# Generated by OpenFakeRAM
VERSION 5.7 ;
BUSBITCHARS "[]" ;
PROPERTYDEFINITIONS
  MACRO width INTEGER ;
  MACRO depth INTEGER ;
  MACRO banks INTEGER ;
END PROPERTYDEFINITIONS
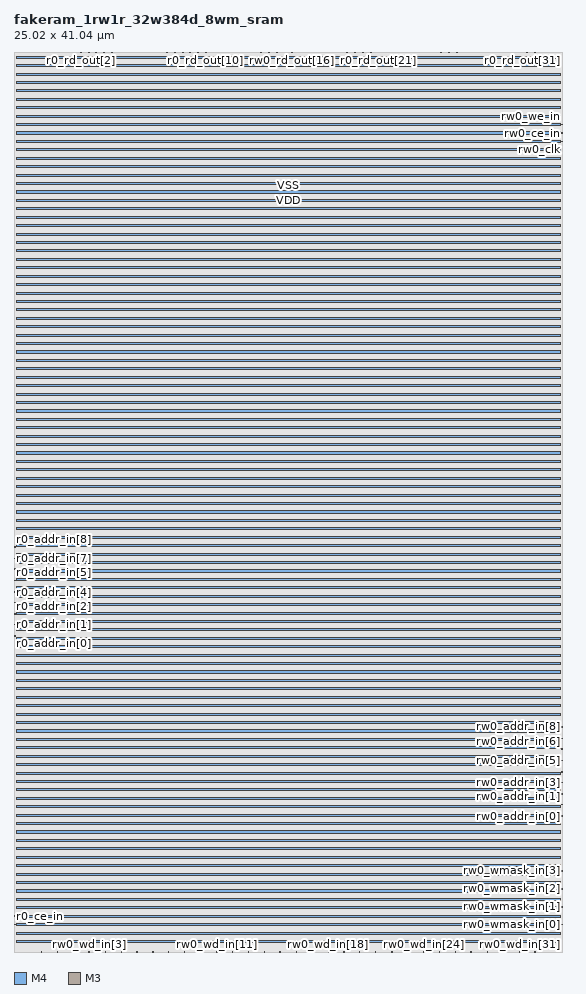
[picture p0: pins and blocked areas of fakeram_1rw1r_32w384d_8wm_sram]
MACRO fakeram_1rw1r_32w384d_8wm_sram
  PROPERTY width 32 ;
  PROPERTY depth 384 ;
  PROPERTY banks 1 ;
  FOREIGN fakeram_1rw1r_32w384d_8wm_sram 0 0 ;
  SYMMETRY X Y R90 ;
  SIZE 25.020 BY 41.040 ;
  CLASS BLOCK ;
  PIN r0_clk
    DIRECTION INPUT ;
    USE SIGNAL ;
    SHAPE ABUTMENT ;
    PORT
      LAYER M4 ;
      RECT 0.000 1.236 0.048 1.260 ;
    END
  END r0_clk
  PIN r0_ce_in
    DIRECTION INPUT ;
    USE SIGNAL ;
    SHAPE ABUTMENT ;
    PORT
      LAYER M4 ;
      RECT 0.000 1.620 0.048 1.644 ;
    END
  END r0_ce_in
  PIN r0_addr_in[0]
    DIRECTION INPUT ;
    USE SIGNAL ;
    SHAPE ABUTMENT ;
    PORT
      LAYER M4 ;
      RECT 0.000 14.388 0.048 14.412 ;
    END
  END r0_addr_in[0]
  PIN r0_addr_in[1]
    DIRECTION INPUT ;
    USE SIGNAL ;
    SHAPE ABUTMENT ;
    PORT
      LAYER M4 ;
      RECT 0.000 14.916 0.048 14.940 ;
    END
  END r0_addr_in[1]
  PIN r0_addr_in[2]
    DIRECTION INPUT ;
    USE SIGNAL ;
    SHAPE ABUTMENT ;
    PORT
      LAYER M4 ;
      RECT 0.000 15.396 0.048 15.420 ;
    END
  END r0_addr_in[2]
  PIN r0_addr_in[3]
    DIRECTION INPUT ;
    USE SIGNAL ;
    SHAPE ABUTMENT ;
    PORT
      LAYER M4 ;
      RECT 0.000 15.924 0.048 15.948 ;
    END
  END r0_addr_in[3]
  PIN r0_addr_in[4]
    DIRECTION INPUT ;
    USE SIGNAL ;
    SHAPE ABUTMENT ;
    PORT
      LAYER M4 ;
      RECT 0.000 16.404 0.048 16.428 ;
    END
  END r0_addr_in[4]
  PIN r0_addr_in[5]
    DIRECTION INPUT ;
    USE SIGNAL ;
    SHAPE ABUTMENT ;
    PORT
      LAYER M4 ;
      RECT 0.000 16.932 0.048 16.956 ;
    END
  END r0_addr_in[5]
  PIN r0_addr_in[6]
    DIRECTION INPUT ;
    USE SIGNAL ;
    SHAPE ABUTMENT ;
    PORT
      LAYER M4 ;
      RECT 0.000 17.460 0.048 17.484 ;
    END
  END r0_addr_in[6]
  PIN r0_addr_in[7]
    DIRECTION INPUT ;
    USE SIGNAL ;
    SHAPE ABUTMENT ;
    PORT
      LAYER M4 ;
      RECT 0.000 17.940 0.048 17.964 ;
    END
  END r0_addr_in[7]
  PIN r0_addr_in[8]
    DIRECTION INPUT ;
    USE SIGNAL ;
    SHAPE ABUTMENT ;
    PORT
      LAYER M4 ;
      RECT 0.000 18.468 0.048 18.492 ;
    END
  END r0_addr_in[8]
  PIN rw0_rd_out[0]
    DIRECTION OUTPUT ;
    USE SIGNAL ;
    SHAPE ABUTMENT ;
    PORT
      LAYER M3 ;
      RECT 1.251 41.004 1.269 41.040 ;
    END
  END rw0_rd_out[0]
  PIN r0_rd_out[0]
    DIRECTION OUTPUT ;
    USE SIGNAL ;
    SHAPE ABUTMENT ;
    PORT
      LAYER M3 ;
      RECT 1.611 41.004 1.629 41.040 ;
    END
  END r0_rd_out[0]
  PIN rw0_rd_out[1]
    DIRECTION OUTPUT ;
    USE SIGNAL ;
    SHAPE ABUTMENT ;
    PORT
      LAYER M3 ;
      RECT 1.971 41.004 1.989 41.040 ;
    END
  END rw0_rd_out[1]
  PIN r0_rd_out[1]
    DIRECTION OUTPUT ;
    USE SIGNAL ;
    SHAPE ABUTMENT ;
    PORT
      LAYER M3 ;
      RECT 2.331 41.004 2.349 41.040 ;
    END
  END r0_rd_out[1]
  PIN rw0_rd_out[2]
    DIRECTION OUTPUT ;
    USE SIGNAL ;
    SHAPE ABUTMENT ;
    PORT
      LAYER M3 ;
      RECT 2.691 41.004 2.709 41.040 ;
    END
  END rw0_rd_out[2]
  PIN r0_rd_out[2]
    DIRECTION OUTPUT ;
    USE SIGNAL ;
    SHAPE ABUTMENT ;
    PORT
      LAYER M3 ;
      RECT 3.051 41.004 3.069 41.040 ;
    END
  END r0_rd_out[2]
  PIN rw0_rd_out[3]
    DIRECTION OUTPUT ;
    USE SIGNAL ;
    SHAPE ABUTMENT ;
    PORT
      LAYER M3 ;
      RECT 3.411 41.004 3.429 41.040 ;
    END
  END rw0_rd_out[3]
  PIN r0_rd_out[3]
    DIRECTION OUTPUT ;
    USE SIGNAL ;
    SHAPE ABUTMENT ;
    PORT
      LAYER M3 ;
      RECT 3.735 41.004 3.753 41.040 ;
    END
  END r0_rd_out[3]
  PIN rw0_rd_out[4]
    DIRECTION OUTPUT ;
    USE SIGNAL ;
    SHAPE ABUTMENT ;
    PORT
      LAYER M3 ;
      RECT 4.095 41.004 4.113 41.040 ;
    END
  END rw0_rd_out[4]
  PIN r0_rd_out[4]
    DIRECTION OUTPUT ;
    USE SIGNAL ;
    SHAPE ABUTMENT ;
    PORT
      LAYER M3 ;
      RECT 4.455 41.004 4.473 41.040 ;
    END
  END r0_rd_out[4]
  PIN rw0_rd_out[5]
    DIRECTION OUTPUT ;
    USE SIGNAL ;
    SHAPE ABUTMENT ;
    PORT
      LAYER M3 ;
      RECT 4.815 41.004 4.833 41.040 ;
    END
  END rw0_rd_out[5]
  PIN r0_rd_out[5]
    DIRECTION OUTPUT ;
    USE SIGNAL ;
    SHAPE ABUTMENT ;
    PORT
      LAYER M3 ;
      RECT 5.175 41.004 5.193 41.040 ;
    END
  END r0_rd_out[5]
  PIN rw0_rd_out[6]
    DIRECTION OUTPUT ;
    USE SIGNAL ;
    SHAPE ABUTMENT ;
    PORT
      LAYER M3 ;
      RECT 5.535 41.004 5.553 41.040 ;
    END
  END rw0_rd_out[6]
  PIN r0_rd_out[6]
    DIRECTION OUTPUT ;
    USE SIGNAL ;
    SHAPE ABUTMENT ;
    PORT
      LAYER M3 ;
      RECT 5.895 41.004 5.913 41.040 ;
    END
  END r0_rd_out[6]
  PIN rw0_rd_out[7]
    DIRECTION OUTPUT ;
    USE SIGNAL ;
    SHAPE ABUTMENT ;
    PORT
      LAYER M3 ;
      RECT 6.255 41.004 6.273 41.040 ;
    END
  END rw0_rd_out[7]
  PIN r0_rd_out[7]
    DIRECTION OUTPUT ;
    USE SIGNAL ;
    SHAPE ABUTMENT ;
    PORT
      LAYER M3 ;
      RECT 6.615 41.004 6.633 41.040 ;
    END
  END r0_rd_out[7]
  PIN rw0_rd_out[8]
    DIRECTION OUTPUT ;
    USE SIGNAL ;
    SHAPE ABUTMENT ;
    PORT
      LAYER M3 ;
      RECT 6.975 41.004 6.993 41.040 ;
    END
  END rw0_rd_out[8]
  PIN r0_rd_out[8]
    DIRECTION OUTPUT ;
    USE SIGNAL ;
    SHAPE ABUTMENT ;
    PORT
      LAYER M3 ;
      RECT 7.335 41.004 7.353 41.040 ;
    END
  END r0_rd_out[8]
  PIN rw0_rd_out[9]
    DIRECTION OUTPUT ;
    USE SIGNAL ;
    SHAPE ABUTMENT ;
    PORT
      LAYER M3 ;
      RECT 7.695 41.004 7.713 41.040 ;
    END
  END rw0_rd_out[9]
  PIN r0_rd_out[9]
    DIRECTION OUTPUT ;
    USE SIGNAL ;
    SHAPE ABUTMENT ;
    PORT
      LAYER M3 ;
      RECT 8.019 41.004 8.037 41.040 ;
    END
  END r0_rd_out[9]
  PIN rw0_rd_out[10]
    DIRECTION OUTPUT ;
    USE SIGNAL ;
    SHAPE ABUTMENT ;
    PORT
      LAYER M3 ;
      RECT 8.379 41.004 8.397 41.040 ;
    END
  END rw0_rd_out[10]
  PIN r0_rd_out[10]
    DIRECTION OUTPUT ;
    USE SIGNAL ;
    SHAPE ABUTMENT ;
    PORT
      LAYER M3 ;
      RECT 8.739 41.004 8.757 41.040 ;
    END
  END r0_rd_out[10]
  PIN rw0_rd_out[11]
    DIRECTION OUTPUT ;
    USE SIGNAL ;
    SHAPE ABUTMENT ;
    PORT
      LAYER M3 ;
      RECT 9.099 41.004 9.117 41.040 ;
    END
  END rw0_rd_out[11]
  PIN r0_rd_out[11]
    DIRECTION OUTPUT ;
    USE SIGNAL ;
    SHAPE ABUTMENT ;
    PORT
      LAYER M3 ;
      RECT 9.459 41.004 9.477 41.040 ;
    END
  END r0_rd_out[11]
  PIN rw0_rd_out[12]
    DIRECTION OUTPUT ;
    USE SIGNAL ;
    SHAPE ABUTMENT ;
    PORT
      LAYER M3 ;
      RECT 9.819 41.004 9.837 41.040 ;
    END
  END rw0_rd_out[12]
  PIN r0_rd_out[12]
    DIRECTION OUTPUT ;
    USE SIGNAL ;
    SHAPE ABUTMENT ;
    PORT
      LAYER M3 ;
      RECT 10.179 41.004 10.197 41.040 ;
    END
  END r0_rd_out[12]
  PIN rw0_rd_out[13]
    DIRECTION OUTPUT ;
    USE SIGNAL ;
    SHAPE ABUTMENT ;
    PORT
      LAYER M3 ;
      RECT 10.539 41.004 10.557 41.040 ;
    END
  END rw0_rd_out[13]
  PIN r0_rd_out[13]
    DIRECTION OUTPUT ;
    USE SIGNAL ;
    SHAPE ABUTMENT ;
    PORT
      LAYER M3 ;
      RECT 10.899 41.004 10.917 41.040 ;
    END
  END r0_rd_out[13]
  PIN rw0_rd_out[14]
    DIRECTION OUTPUT ;
    USE SIGNAL ;
    SHAPE ABUTMENT ;
    PORT
      LAYER M3 ;
      RECT 11.259 41.004 11.277 41.040 ;
    END
  END rw0_rd_out[14]
  PIN r0_rd_out[14]
    DIRECTION OUTPUT ;
    USE SIGNAL ;
    SHAPE ABUTMENT ;
    PORT
      LAYER M3 ;
      RECT 11.619 41.004 11.637 41.040 ;
    END
  END r0_rd_out[14]
  PIN rw0_rd_out[15]
    DIRECTION OUTPUT ;
    USE SIGNAL ;
    SHAPE ABUTMENT ;
    PORT
      LAYER M3 ;
      RECT 11.979 41.004 11.997 41.040 ;
    END
  END rw0_rd_out[15]
  PIN r0_rd_out[15]
    DIRECTION OUTPUT ;
    USE SIGNAL ;
    SHAPE ABUTMENT ;
    PORT
      LAYER M3 ;
      RECT 12.339 41.004 12.357 41.040 ;
    END
  END r0_rd_out[15]
  PIN rw0_rd_out[16]
    DIRECTION OUTPUT ;
    USE SIGNAL ;
    SHAPE ABUTMENT ;
    PORT
      LAYER M3 ;
      RECT 12.663 41.004 12.681 41.040 ;
    END
  END rw0_rd_out[16]
  PIN r0_rd_out[16]
    DIRECTION OUTPUT ;
    USE SIGNAL ;
    SHAPE ABUTMENT ;
    PORT
      LAYER M3 ;
      RECT 13.023 41.004 13.041 41.040 ;
    END
  END r0_rd_out[16]
  PIN rw0_rd_out[17]
    DIRECTION OUTPUT ;
    USE SIGNAL ;
    SHAPE ABUTMENT ;
    PORT
      LAYER M3 ;
      RECT 13.383 41.004 13.401 41.040 ;
    END
  END rw0_rd_out[17]
  PIN r0_rd_out[17]
    DIRECTION OUTPUT ;
    USE SIGNAL ;
    SHAPE ABUTMENT ;
    PORT
      LAYER M3 ;
      RECT 13.743 41.004 13.761 41.040 ;
    END
  END r0_rd_out[17]
  PIN rw0_rd_out[18]
    DIRECTION OUTPUT ;
    USE SIGNAL ;
    SHAPE ABUTMENT ;
    PORT
      LAYER M3 ;
      RECT 14.103 41.004 14.121 41.040 ;
    END
  END rw0_rd_out[18]
  PIN r0_rd_out[18]
    DIRECTION OUTPUT ;
    USE SIGNAL ;
    SHAPE ABUTMENT ;
    PORT
      LAYER M3 ;
      RECT 14.463 41.004 14.481 41.040 ;
    END
  END r0_rd_out[18]
  PIN rw0_rd_out[19]
    DIRECTION OUTPUT ;
    USE SIGNAL ;
    SHAPE ABUTMENT ;
    PORT
      LAYER M3 ;
      RECT 14.823 41.004 14.841 41.040 ;
    END
  END rw0_rd_out[19]
  PIN r0_rd_out[19]
    DIRECTION OUTPUT ;
    USE SIGNAL ;
    SHAPE ABUTMENT ;
    PORT
      LAYER M3 ;
      RECT 15.183 41.004 15.201 41.040 ;
    END
  END r0_rd_out[19]
  PIN rw0_rd_out[20]
    DIRECTION OUTPUT ;
    USE SIGNAL ;
    SHAPE ABUTMENT ;
    PORT
      LAYER M3 ;
      RECT 15.543 41.004 15.561 41.040 ;
    END
  END rw0_rd_out[20]
  PIN r0_rd_out[20]
    DIRECTION OUTPUT ;
    USE SIGNAL ;
    SHAPE ABUTMENT ;
    PORT
      LAYER M3 ;
      RECT 15.903 41.004 15.921 41.040 ;
    END
  END r0_rd_out[20]
  PIN rw0_rd_out[21]
    DIRECTION OUTPUT ;
    USE SIGNAL ;
    SHAPE ABUTMENT ;
    PORT
      LAYER M3 ;
      RECT 16.263 41.004 16.281 41.040 ;
    END
  END rw0_rd_out[21]
  PIN r0_rd_out[21]
    DIRECTION OUTPUT ;
    USE SIGNAL ;
    SHAPE ABUTMENT ;
    PORT
      LAYER M3 ;
      RECT 16.623 41.004 16.641 41.040 ;
    END
  END r0_rd_out[21]
  PIN rw0_rd_out[22]
    DIRECTION OUTPUT ;
    USE SIGNAL ;
    SHAPE ABUTMENT ;
    PORT
      LAYER M3 ;
      RECT 16.983 41.004 17.001 41.040 ;
    END
  END rw0_rd_out[22]
  PIN r0_rd_out[22]
    DIRECTION OUTPUT ;
    USE SIGNAL ;
    SHAPE ABUTMENT ;
    PORT
      LAYER M3 ;
      RECT 17.307 41.004 17.325 41.040 ;
    END
  END r0_rd_out[22]
  PIN rw0_rd_out[23]
    DIRECTION OUTPUT ;
    USE SIGNAL ;
    SHAPE ABUTMENT ;
    PORT
      LAYER M3 ;
      RECT 17.667 41.004 17.685 41.040 ;
    END
  END rw0_rd_out[23]
  PIN r0_rd_out[23]
    DIRECTION OUTPUT ;
    USE SIGNAL ;
    SHAPE ABUTMENT ;
    PORT
      LAYER M3 ;
      RECT 18.027 41.004 18.045 41.040 ;
    END
  END r0_rd_out[23]
  PIN rw0_rd_out[24]
    DIRECTION OUTPUT ;
    USE SIGNAL ;
    SHAPE ABUTMENT ;
    PORT
      LAYER M3 ;
      RECT 18.387 41.004 18.405 41.040 ;
    END
  END rw0_rd_out[24]
  PIN r0_rd_out[24]
    DIRECTION OUTPUT ;
    USE SIGNAL ;
    SHAPE ABUTMENT ;
    PORT
      LAYER M3 ;
      RECT 18.747 41.004 18.765 41.040 ;
    END
  END r0_rd_out[24]
  PIN rw0_rd_out[25]
    DIRECTION OUTPUT ;
    USE SIGNAL ;
    SHAPE ABUTMENT ;
    PORT
      LAYER M3 ;
      RECT 19.107 41.004 19.125 41.040 ;
    END
  END rw0_rd_out[25]
  PIN r0_rd_out[25]
    DIRECTION OUTPUT ;
    USE SIGNAL ;
    SHAPE ABUTMENT ;
    PORT
      LAYER M3 ;
      RECT 19.467 41.004 19.485 41.040 ;
    END
  END r0_rd_out[25]
  PIN rw0_rd_out[26]
    DIRECTION OUTPUT ;
    USE SIGNAL ;
    SHAPE ABUTMENT ;
    PORT
      LAYER M3 ;
      RECT 19.827 41.004 19.845 41.040 ;
    END
  END rw0_rd_out[26]
  PIN r0_rd_out[26]
    DIRECTION OUTPUT ;
    USE SIGNAL ;
    SHAPE ABUTMENT ;
    PORT
      LAYER M3 ;
      RECT 20.187 41.004 20.205 41.040 ;
    END
  END r0_rd_out[26]
  PIN rw0_rd_out[27]
    DIRECTION OUTPUT ;
    USE SIGNAL ;
    SHAPE ABUTMENT ;
    PORT
      LAYER M3 ;
      RECT 20.547 41.004 20.565 41.040 ;
    END
  END rw0_rd_out[27]
  PIN r0_rd_out[27]
    DIRECTION OUTPUT ;
    USE SIGNAL ;
    SHAPE ABUTMENT ;
    PORT
      LAYER M3 ;
      RECT 20.907 41.004 20.925 41.040 ;
    END
  END r0_rd_out[27]
  PIN rw0_rd_out[28]
    DIRECTION OUTPUT ;
    USE SIGNAL ;
    SHAPE ABUTMENT ;
    PORT
      LAYER M3 ;
      RECT 21.267 41.004 21.285 41.040 ;
    END
  END rw0_rd_out[28]
  PIN r0_rd_out[28]
    DIRECTION OUTPUT ;
    USE SIGNAL ;
    SHAPE ABUTMENT ;
    PORT
      LAYER M3 ;
      RECT 21.591 41.004 21.609 41.040 ;
    END
  END r0_rd_out[28]
  PIN rw0_rd_out[29]
    DIRECTION OUTPUT ;
    USE SIGNAL ;
    SHAPE ABUTMENT ;
    PORT
      LAYER M3 ;
      RECT 21.951 41.004 21.969 41.040 ;
    END
  END rw0_rd_out[29]
  PIN r0_rd_out[29]
    DIRECTION OUTPUT ;
    USE SIGNAL ;
    SHAPE ABUTMENT ;
    PORT
      LAYER M3 ;
      RECT 22.311 41.004 22.329 41.040 ;
    END
  END r0_rd_out[29]
  PIN rw0_rd_out[30]
    DIRECTION OUTPUT ;
    USE SIGNAL ;
    SHAPE ABUTMENT ;
    PORT
      LAYER M3 ;
      RECT 22.671 41.004 22.689 41.040 ;
    END
  END rw0_rd_out[30]
  PIN r0_rd_out[30]
    DIRECTION OUTPUT ;
    USE SIGNAL ;
    SHAPE ABUTMENT ;
    PORT
      LAYER M3 ;
      RECT 23.031 41.004 23.049 41.040 ;
    END
  END r0_rd_out[30]
  PIN rw0_rd_out[31]
    DIRECTION OUTPUT ;
    USE SIGNAL ;
    SHAPE ABUTMENT ;
    PORT
      LAYER M3 ;
      RECT 23.391 41.004 23.409 41.040 ;
    END
  END rw0_rd_out[31]
  PIN r0_rd_out[31]
    DIRECTION OUTPUT ;
    USE SIGNAL ;
    SHAPE ABUTMENT ;
    PORT
      LAYER M3 ;
      RECT 23.751 41.004 23.769 41.040 ;
    END
  END r0_rd_out[31]
  PIN rw0_clk
    DIRECTION INPUT ;
    USE SIGNAL ;
    SHAPE ABUTMENT ;
    PORT
      LAYER M4 ;
      RECT 24.972 36.948 25.020 36.972 ;
    END
  END rw0_clk
  PIN rw0_ce_in
    DIRECTION INPUT ;
    USE SIGNAL ;
    SHAPE ABUTMENT ;
    PORT
      LAYER M4 ;
      RECT 24.972 37.332 25.020 37.356 ;
    END
  END rw0_ce_in
  PIN rw0_we_in
    DIRECTION INPUT ;
    USE SIGNAL ;
    SHAPE ABUTMENT ;
    PORT
      LAYER M4 ;
      RECT 24.972 37.716 25.020 37.740 ;
    END
  END rw0_we_in
  PIN rw0_addr_in[0]
    DIRECTION INPUT ;
    USE SIGNAL ;
    SHAPE ABUTMENT ;
    PORT
      LAYER M4 ;
      RECT 24.972 6.180 25.020 6.204 ;
    END
  END rw0_addr_in[0]
  PIN rw0_addr_in[1]
    DIRECTION INPUT ;
    USE SIGNAL ;
    SHAPE ABUTMENT ;
    PORT
      LAYER M4 ;
      RECT 24.972 6.708 25.020 6.732 ;
    END
  END rw0_addr_in[1]
  PIN rw0_addr_in[2]
    DIRECTION INPUT ;
    USE SIGNAL ;
    SHAPE ABUTMENT ;
    PORT
      LAYER M4 ;
      RECT 24.972 7.188 25.020 7.212 ;
    END
  END rw0_addr_in[2]
  PIN rw0_addr_in[3]
    DIRECTION INPUT ;
    USE SIGNAL ;
    SHAPE ABUTMENT ;
    PORT
      LAYER M4 ;
      RECT 24.972 7.716 25.020 7.740 ;
    END
  END rw0_addr_in[3]
  PIN rw0_addr_in[4]
    DIRECTION INPUT ;
    USE SIGNAL ;
    SHAPE ABUTMENT ;
    PORT
      LAYER M4 ;
      RECT 24.972 8.196 25.020 8.220 ;
    END
  END rw0_addr_in[4]
  PIN rw0_addr_in[5]
    DIRECTION INPUT ;
    USE SIGNAL ;
    SHAPE ABUTMENT ;
    PORT
      LAYER M4 ;
      RECT 24.972 8.724 25.020 8.748 ;
    END
  END rw0_addr_in[5]
  PIN rw0_addr_in[6]
    DIRECTION INPUT ;
    USE SIGNAL ;
    SHAPE ABUTMENT ;
    PORT
      LAYER M4 ;
      RECT 24.972 9.252 25.020 9.276 ;
    END
  END rw0_addr_in[6]
  PIN rw0_addr_in[7]
    DIRECTION INPUT ;
    USE SIGNAL ;
    SHAPE ABUTMENT ;
    PORT
      LAYER M4 ;
      RECT 24.972 9.732 25.020 9.756 ;
    END
  END rw0_addr_in[7]
  PIN rw0_addr_in[8]
    DIRECTION INPUT ;
    USE SIGNAL ;
    SHAPE ABUTMENT ;
    PORT
      LAYER M4 ;
      RECT 24.972 10.260 25.020 10.284 ;
    END
  END rw0_addr_in[8]
  PIN rw0_wmask_in[0]
    DIRECTION INPUT ;
    USE SIGNAL ;
    SHAPE ABUTMENT ;
    PORT
      LAYER M4 ;
      RECT 24.972 1.236 25.020 1.260 ;
    END
  END rw0_wmask_in[0]
  PIN rw0_wmask_in[1]
    DIRECTION INPUT ;
    USE SIGNAL ;
    SHAPE ABUTMENT ;
    PORT
      LAYER M4 ;
      RECT 24.972 2.052 25.020 2.076 ;
    END
  END rw0_wmask_in[1]
  PIN rw0_wmask_in[2]
    DIRECTION INPUT ;
    USE SIGNAL ;
    SHAPE ABUTMENT ;
    PORT
      LAYER M4 ;
      RECT 24.972 2.868 25.020 2.892 ;
    END
  END rw0_wmask_in[2]
  PIN rw0_wmask_in[3]
    DIRECTION INPUT ;
    USE SIGNAL ;
    SHAPE ABUTMENT ;
    PORT
      LAYER M4 ;
      RECT 24.972 3.684 25.020 3.708 ;
    END
  END rw0_wmask_in[3]
  PIN rw0_wd_in[0]
    DIRECTION INPUT ;
    USE SIGNAL ;
    SHAPE ABUTMENT ;
    PORT
      LAYER M3 ;
      RECT 1.251 0.000 1.269 0.036 ;
    END
  END rw0_wd_in[0]
  PIN rw0_wd_in[1]
    DIRECTION INPUT ;
    USE SIGNAL ;
    SHAPE ABUTMENT ;
    PORT
      LAYER M3 ;
      RECT 1.971 0.000 1.989 0.036 ;
    END
  END rw0_wd_in[1]
  PIN rw0_wd_in[2]
    DIRECTION INPUT ;
    USE SIGNAL ;
    SHAPE ABUTMENT ;
    PORT
      LAYER M3 ;
      RECT 2.691 0.000 2.709 0.036 ;
    END
  END rw0_wd_in[2]
  PIN rw0_wd_in[3]
    DIRECTION INPUT ;
    USE SIGNAL ;
    SHAPE ABUTMENT ;
    PORT
      LAYER M3 ;
      RECT 3.411 0.000 3.429 0.036 ;
    END
  END rw0_wd_in[3]
  PIN rw0_wd_in[4]
    DIRECTION INPUT ;
    USE SIGNAL ;
    SHAPE ABUTMENT ;
    PORT
      LAYER M3 ;
      RECT 4.167 0.000 4.185 0.036 ;
    END
  END rw0_wd_in[4]
  PIN rw0_wd_in[5]
    DIRECTION INPUT ;
    USE SIGNAL ;
    SHAPE ABUTMENT ;
    PORT
      LAYER M3 ;
      RECT 4.887 0.000 4.905 0.036 ;
    END
  END rw0_wd_in[5]
  PIN rw0_wd_in[6]
    DIRECTION INPUT ;
    USE SIGNAL ;
    SHAPE ABUTMENT ;
    PORT
      LAYER M3 ;
      RECT 5.607 0.000 5.625 0.036 ;
    END
  END rw0_wd_in[6]
  PIN rw0_wd_in[7]
    DIRECTION INPUT ;
    USE SIGNAL ;
    SHAPE ABUTMENT ;
    PORT
      LAYER M3 ;
      RECT 6.327 0.000 6.345 0.036 ;
    END
  END rw0_wd_in[7]
  PIN rw0_wd_in[8]
    DIRECTION INPUT ;
    USE SIGNAL ;
    SHAPE ABUTMENT ;
    PORT
      LAYER M3 ;
      RECT 7.047 0.000 7.065 0.036 ;
    END
  END rw0_wd_in[8]
  PIN rw0_wd_in[9]
    DIRECTION INPUT ;
    USE SIGNAL ;
    SHAPE ABUTMENT ;
    PORT
      LAYER M3 ;
      RECT 7.767 0.000 7.785 0.036 ;
    END
  END rw0_wd_in[9]
  PIN rw0_wd_in[10]
    DIRECTION INPUT ;
    USE SIGNAL ;
    SHAPE ABUTMENT ;
    PORT
      LAYER M3 ;
      RECT 8.523 0.000 8.541 0.036 ;
    END
  END rw0_wd_in[10]
  PIN rw0_wd_in[11]
    DIRECTION INPUT ;
    USE SIGNAL ;
    SHAPE ABUTMENT ;
    PORT
      LAYER M3 ;
      RECT 9.243 0.000 9.261 0.036 ;
    END
  END rw0_wd_in[11]
  PIN rw0_wd_in[12]
    DIRECTION INPUT ;
    USE SIGNAL ;
    SHAPE ABUTMENT ;
    PORT
      LAYER M3 ;
      RECT 9.963 0.000 9.981 0.036 ;
    END
  END rw0_wd_in[12]
  PIN rw0_wd_in[13]
    DIRECTION INPUT ;
    USE SIGNAL ;
    SHAPE ABUTMENT ;
    PORT
      LAYER M3 ;
      RECT 10.683 0.000 10.701 0.036 ;
    END
  END rw0_wd_in[13]
  PIN rw0_wd_in[14]
    DIRECTION INPUT ;
    USE SIGNAL ;
    SHAPE ABUTMENT ;
    PORT
      LAYER M3 ;
      RECT 11.403 0.000 11.421 0.036 ;
    END
  END rw0_wd_in[14]
  PIN rw0_wd_in[15]
    DIRECTION INPUT ;
    USE SIGNAL ;
    SHAPE ABUTMENT ;
    PORT
      LAYER M3 ;
      RECT 12.123 0.000 12.141 0.036 ;
    END
  END rw0_wd_in[15]
  PIN rw0_wd_in[16]
    DIRECTION INPUT ;
    USE SIGNAL ;
    SHAPE ABUTMENT ;
    PORT
      LAYER M3 ;
      RECT 12.879 0.000 12.897 0.036 ;
    END
  END rw0_wd_in[16]
  PIN rw0_wd_in[17]
    DIRECTION INPUT ;
    USE SIGNAL ;
    SHAPE ABUTMENT ;
    PORT
      LAYER M3 ;
      RECT 13.599 0.000 13.617 0.036 ;
    END
  END rw0_wd_in[17]
  PIN rw0_wd_in[18]
    DIRECTION INPUT ;
    USE SIGNAL ;
    SHAPE ABUTMENT ;
    PORT
      LAYER M3 ;
      RECT 14.319 0.000 14.337 0.036 ;
    END
  END rw0_wd_in[18]
  PIN rw0_wd_in[19]
    DIRECTION INPUT ;
    USE SIGNAL ;
    SHAPE ABUTMENT ;
    PORT
      LAYER M3 ;
      RECT 15.039 0.000 15.057 0.036 ;
    END
  END rw0_wd_in[19]
  PIN rw0_wd_in[20]
    DIRECTION INPUT ;
    USE SIGNAL ;
    SHAPE ABUTMENT ;
    PORT
      LAYER M3 ;
      RECT 15.759 0.000 15.777 0.036 ;
    END
  END rw0_wd_in[20]
  PIN rw0_wd_in[21]
    DIRECTION INPUT ;
    USE SIGNAL ;
    SHAPE ABUTMENT ;
    PORT
      LAYER M3 ;
      RECT 16.479 0.000 16.497 0.036 ;
    END
  END rw0_wd_in[21]
  PIN rw0_wd_in[22]
    DIRECTION INPUT ;
    USE SIGNAL ;
    SHAPE ABUTMENT ;
    PORT
      LAYER M3 ;
      RECT 17.235 0.000 17.253 0.036 ;
    END
  END rw0_wd_in[22]
  PIN rw0_wd_in[23]
    DIRECTION INPUT ;
    USE SIGNAL ;
    SHAPE ABUTMENT ;
    PORT
      LAYER M3 ;
      RECT 17.955 0.000 17.973 0.036 ;
    END
  END rw0_wd_in[23]
  PIN rw0_wd_in[24]
    DIRECTION INPUT ;
    USE SIGNAL ;
    SHAPE ABUTMENT ;
    PORT
      LAYER M3 ;
      RECT 18.675 0.000 18.693 0.036 ;
    END
  END rw0_wd_in[24]
  PIN rw0_wd_in[25]
    DIRECTION INPUT ;
    USE SIGNAL ;
    SHAPE ABUTMENT ;
    PORT
      LAYER M3 ;
      RECT 19.395 0.000 19.413 0.036 ;
    END
  END rw0_wd_in[25]
  PIN rw0_wd_in[26]
    DIRECTION INPUT ;
    USE SIGNAL ;
    SHAPE ABUTMENT ;
    PORT
      LAYER M3 ;
      RECT 20.115 0.000 20.133 0.036 ;
    END
  END rw0_wd_in[26]
  PIN rw0_wd_in[27]
    DIRECTION INPUT ;
    USE SIGNAL ;
    SHAPE ABUTMENT ;
    PORT
      LAYER M3 ;
      RECT 20.835 0.000 20.853 0.036 ;
    END
  END rw0_wd_in[27]
  PIN rw0_wd_in[28]
    DIRECTION INPUT ;
    USE SIGNAL ;
    SHAPE ABUTMENT ;
    PORT
      LAYER M3 ;
      RECT 21.591 0.000 21.609 0.036 ;
    END
  END rw0_wd_in[28]
  PIN rw0_wd_in[29]
    DIRECTION INPUT ;
    USE SIGNAL ;
    SHAPE ABUTMENT ;
    PORT
      LAYER M3 ;
      RECT 22.311 0.000 22.329 0.036 ;
    END
  END rw0_wd_in[29]
  PIN rw0_wd_in[30]
    DIRECTION INPUT ;
    USE SIGNAL ;
    SHAPE ABUTMENT ;
    PORT
      LAYER M3 ;
      RECT 23.031 0.000 23.049 0.036 ;
    END
  END rw0_wd_in[30]
  PIN rw0_wd_in[31]
    DIRECTION INPUT ;
    USE SIGNAL ;
    SHAPE ABUTMENT ;
    PORT
      LAYER M3 ;
      RECT 23.751 0.000 23.769 0.036 ;
    END
  END rw0_wd_in[31]
  PIN VSS
    DIRECTION INOUT ;
    USE GROUND ;
    PORT
      LAYER M4 ;
      RECT 0.096 0.816 24.924 0.912 ;
      RECT 0.096 1.584 24.924 1.680 ;
      RECT 0.096 2.352 24.924 2.448 ;
      RECT 0.096 3.120 24.924 3.216 ;
      RECT 0.096 3.888 24.924 3.984 ;
      RECT 0.096 4.656 24.924 4.752 ;
      RECT 0.096 5.424 24.924 5.520 ;
      RECT 0.096 6.192 24.924 6.288 ;
      RECT 0.096 6.960 24.924 7.056 ;
      RECT 0.096 7.728 24.924 7.824 ;
      RECT 0.096 8.496 24.924 8.592 ;
      RECT 0.096 9.264 24.924 9.360 ;
      RECT 0.096 10.032 24.924 10.128 ;
      RECT 0.096 10.800 24.924 10.896 ;
      RECT 0.096 11.568 24.924 11.664 ;
      RECT 0.096 12.336 24.924 12.432 ;
      RECT 0.096 13.104 24.924 13.200 ;
      RECT 0.096 13.872 24.924 13.968 ;
      RECT 0.096 14.640 24.924 14.736 ;
      RECT 0.096 15.408 24.924 15.504 ;
      RECT 0.096 16.176 24.924 16.272 ;
      RECT 0.096 16.944 24.924 17.040 ;
      RECT 0.096 17.712 24.924 17.808 ;
      RECT 0.096 18.480 24.924 18.576 ;
      RECT 0.096 19.248 24.924 19.344 ;
      RECT 0.096 20.016 24.924 20.112 ;
      RECT 0.096 20.784 24.924 20.880 ;
      RECT 0.096 21.552 24.924 21.648 ;
      RECT 0.096 22.320 24.924 22.416 ;
      RECT 0.096 23.088 24.924 23.184 ;
      RECT 0.096 23.856 24.924 23.952 ;
      RECT 0.096 24.624 24.924 24.720 ;
      RECT 0.096 25.392 24.924 25.488 ;
      RECT 0.096 26.160 24.924 26.256 ;
      RECT 0.096 26.928 24.924 27.024 ;
      RECT 0.096 27.696 24.924 27.792 ;
      RECT 0.096 28.464 24.924 28.560 ;
      RECT 0.096 29.232 24.924 29.328 ;
      RECT 0.096 30.000 24.924 30.096 ;
      RECT 0.096 30.768 24.924 30.864 ;
      RECT 0.096 31.536 24.924 31.632 ;
      RECT 0.096 32.304 24.924 32.400 ;
      RECT 0.096 33.072 24.924 33.168 ;
      RECT 0.096 33.840 24.924 33.936 ;
      RECT 0.096 34.608 24.924 34.704 ;
      RECT 0.096 35.376 24.924 35.472 ;
      RECT 0.096 36.144 24.924 36.240 ;
      RECT 0.096 36.912 24.924 37.008 ;
      RECT 0.096 37.680 24.924 37.776 ;
      RECT 0.096 38.448 24.924 38.544 ;
      RECT 0.096 39.216 24.924 39.312 ;
      RECT 0.096 39.984 24.924 40.080 ;
      RECT 0.096 40.752 24.924 40.848 ;
    END
  END VSS
  PIN VDD
    DIRECTION INOUT ;
    USE POWER ;
    PORT
      LAYER M4 ;
      RECT 0.096 0.432 24.924 0.528 ;
      RECT 0.096 1.200 24.924 1.296 ;
      RECT 0.096 1.968 24.924 2.064 ;
      RECT 0.096 2.736 24.924 2.832 ;
      RECT 0.096 3.504 24.924 3.600 ;
      RECT 0.096 4.272 24.924 4.368 ;
      RECT 0.096 5.040 24.924 5.136 ;
      RECT 0.096 5.808 24.924 5.904 ;
      RECT 0.096 6.576 24.924 6.672 ;
      RECT 0.096 7.344 24.924 7.440 ;
      RECT 0.096 8.112 24.924 8.208 ;
      RECT 0.096 8.880 24.924 8.976 ;
      RECT 0.096 9.648 24.924 9.744 ;
      RECT 0.096 10.416 24.924 10.512 ;
      RECT 0.096 11.184 24.924 11.280 ;
      RECT 0.096 11.952 24.924 12.048 ;
      RECT 0.096 12.720 24.924 12.816 ;
      RECT 0.096 13.488 24.924 13.584 ;
      RECT 0.096 14.256 24.924 14.352 ;
      RECT 0.096 15.024 24.924 15.120 ;
      RECT 0.096 15.792 24.924 15.888 ;
      RECT 0.096 16.560 24.924 16.656 ;
      RECT 0.096 17.328 24.924 17.424 ;
      RECT 0.096 18.096 24.924 18.192 ;
      RECT 0.096 18.864 24.924 18.960 ;
      RECT 0.096 19.632 24.924 19.728 ;
      RECT 0.096 20.400 24.924 20.496 ;
      RECT 0.096 21.168 24.924 21.264 ;
      RECT 0.096 21.936 24.924 22.032 ;
      RECT 0.096 22.704 24.924 22.800 ;
      RECT 0.096 23.472 24.924 23.568 ;
      RECT 0.096 24.240 24.924 24.336 ;
      RECT 0.096 25.008 24.924 25.104 ;
      RECT 0.096 25.776 24.924 25.872 ;
      RECT 0.096 26.544 24.924 26.640 ;
      RECT 0.096 27.312 24.924 27.408 ;
      RECT 0.096 28.080 24.924 28.176 ;
      RECT 0.096 28.848 24.924 28.944 ;
      RECT 0.096 29.616 24.924 29.712 ;
      RECT 0.096 30.384 24.924 30.480 ;
      RECT 0.096 31.152 24.924 31.248 ;
      RECT 0.096 31.920 24.924 32.016 ;
      RECT 0.096 32.688 24.924 32.784 ;
      RECT 0.096 33.456 24.924 33.552 ;
      RECT 0.096 34.224 24.924 34.320 ;
      RECT 0.096 34.992 24.924 35.088 ;
      RECT 0.096 35.760 24.924 35.856 ;
      RECT 0.096 36.528 24.924 36.624 ;
      RECT 0.096 37.296 24.924 37.392 ;
      RECT 0.096 38.064 24.924 38.160 ;
      RECT 0.096 38.832 24.924 38.928 ;
      RECT 0.096 39.600 24.924 39.696 ;
      RECT 0.096 40.368 24.924 40.464 ;
    END
  END VDD
  OBS
    LAYER M1 ;
    RECT 0 0 25.020 41.040 ;
    LAYER M2 ;
    RECT 0 0 25.020 41.040 ;
    LAYER M3 ;
    RECT 0 0 25.020 41.040 ;
    LAYER M4 ;
    RECT 0 0 25.020 41.040 ;
  END
END fakeram_1rw1r_32w384d_8wm_sram

END LIBRARY
